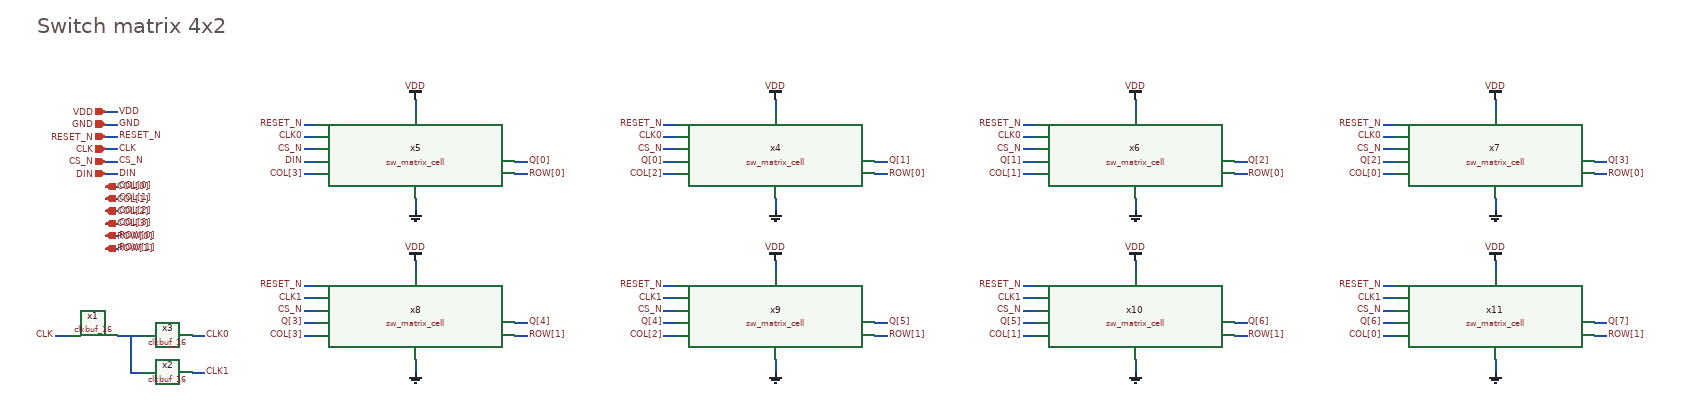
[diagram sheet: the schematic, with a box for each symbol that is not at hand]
v {xschem version=3.4.8RC file_version=1.3
* Copyright 2022 GlobalFoundries PDK Authors
*
* Licensed under the Apache License, Version 2.0 (the "License");
* you may not use this file except in compliance with the License.
* You may obtain a copy of the License at
*
*     https://www.apache.org/licenses/LICENSE-2.0
*
* Unless required by applicable law or agreed to in writing, software
* distributed under the License is distributed on an "AS IS" BASIS,
* WITHOUT WARRANTIES OR CONDITIONS OF ANY KIND, either express or implied.
* See the License for the specific language governing permissions and
* limitations under the License.

}
G {}
K {}
V {}
S {}
F {}
E {}
T {Switch matrix 4x2} 70 -790 0 0 1 1 {}
N 680 -660 680 -640 {lab=VDD}
N 680 -500 680 -480 {lab=GND}
N 500 -620 520 -620 {lab=RESET_N}
N 500 -600 520 -600 {lab=CLK0}
N 500 -580 520 -580 {lab=CS_N}
N 500 -560 520 -560 {lab=DIN}
N 100 -280 120 -280 {lab=CLK}
N 200 -280 240 -280 {lab=#net5}
N 320 -280 340 -280 {lab=CLK0}
N 500 -540 520 -540 {lab=COL[3]}
N 840 -540 860 -540 {lab=ROW[0]}
N 840 -560 860 -560 {lab=Q[0]}
N 320 -220 340 -220 {lab=CLK1}
N 220 -220 240 -220 {lab=#net5}
N 220 -280 220 -220 {lab=#net5}
N 1260 -660 1260 -640 {lab=VDD}
N 1260 -500 1260 -480 {lab=GND}
N 1080 -620 1100 -620 {lab=RESET_N}
N 1080 -600 1100 -600 {lab=CLK0}
N 1080 -580 1100 -580 {lab=CS_N}
N 1080 -560 1100 -560 {lab=Q[0]}
N 1080 -540 1100 -540 {lab=COL[2]}
N 1420 -540 1440 -540 {lab=ROW[0]}
N 1420 -560 1440 -560 {lab=Q[1]}
N 1840 -660 1840 -640 {lab=VDD}
N 1840 -500 1840 -480 {lab=GND}
N 1660 -620 1680 -620 {lab=RESET_N}
N 1660 -600 1680 -600 {lab=CLK0}
N 1660 -580 1680 -580 {lab=CS_N}
N 1660 -560 1680 -560 {lab=Q[1]}
N 1660 -540 1680 -540 {lab=COL[1]}
N 2000 -540 2020 -540 {lab=ROW[0]}
N 2000 -560 2020 -560 {lab=Q[2]}
N 2420 -660 2420 -640 {lab=VDD}
N 2420 -500 2420 -480 {lab=GND}
N 2240 -620 2260 -620 {lab=RESET_N}
N 2240 -600 2260 -600 {lab=CLK0}
N 2240 -580 2260 -580 {lab=CS_N}
N 2240 -560 2260 -560 {lab=Q[2]}
N 2240 -540 2260 -540 {lab=COL[0]}
N 2580 -540 2600 -540 {lab=ROW[0]}
N 2580 -560 2600 -560 {lab=Q[3]}
N 680 -400 680 -380 {lab=VDD}
N 680 -240 680 -220 {lab=GND}
N 500 -360 520 -360 {lab=RESET_N}
N 500 -340 520 -340 {lab=CLK1}
N 500 -320 520 -320 {lab=CS_N}
N 500 -300 520 -300 {lab=Q[3]}
N 500 -280 520 -280 {lab=COL[3]}
N 840 -280 860 -280 {lab=ROW[1]}
N 840 -300 860 -300 {lab=Q[4]}
N 1260 -400 1260 -380 {lab=VDD}
N 1260 -240 1260 -220 {lab=GND}
N 1080 -360 1100 -360 {lab=RESET_N}
N 1080 -340 1100 -340 {lab=CLK1}
N 1080 -320 1100 -320 {lab=CS_N}
N 1080 -300 1100 -300 {lab=Q[4]}
N 1080 -280 1100 -280 {lab=COL[2]}
N 1420 -280 1440 -280 {lab=ROW[1]}
N 1420 -300 1440 -300 {lab=Q[5]}
N 1840 -400 1840 -380 {lab=VDD}
N 1840 -240 1840 -220 {lab=GND}
N 1660 -360 1680 -360 {lab=RESET_N}
N 1660 -340 1680 -340 {lab=CLK1}
N 1660 -320 1680 -320 {lab=CS_N}
N 1660 -300 1680 -300 {lab=Q[5]}
N 1660 -280 1680 -280 {lab=COL[1]}
N 2000 -280 2020 -280 {lab=ROW[1]}
N 2000 -300 2020 -300 {lab=Q[6]}
N 2420 -400 2420 -380 {lab=VDD}
N 2420 -240 2420 -220 {lab=GND}
N 2240 -360 2260 -360 {lab=RESET_N}
N 2240 -340 2260 -340 {lab=CLK1}
N 2240 -320 2260 -320 {lab=CS_N}
N 2240 -300 2260 -300 {lab=Q[6]}
N 2240 -280 2260 -280 {lab=COL[0]}
N 2580 -280 2600 -280 {lab=ROW[1]}
N 2580 -300 2600 -300 {lab=Q[7]}
N 180 -600 200 -600 {lab=RESET_N}
N 180 -580 200 -580 {lab=CLK}
N 180 -560 200 -560 {lab=CS_N}
N 180 -540 200 -540 {lab=DIN}
N 180 -520 200 -520 {lab=COL[0]}
N 180 -620 200 -620 {lab=GND}
N 180 -640 200 -640 {lab=VDD}
N 180 -500 200 -500 {lab=COL[1]}
N 180 -480 200 -480 {lab=COL[3]}
N 180 -460 200 -460 {lab=COL[3]}
N 180 -440 200 -440 {lab=COL[0]}
N 180 -420 200 -420 {lab=COL[1]}
C {devices/title.sym} 160 -30 0 0 {name=l5 author="Yutaka KOTANI"}
C {gnd.sym} 680 -480 0 0 {name=l7 lab=GND}
C {vdd.sym} 680 -660 0 0 {name=l8 lab=VDD}
C {lab_pin.sym} 500 -620 0 0 {name=p6 sig_type=std_logic lab=RESET_N}
C {lab_pin.sym} 860 -540 0 1 {name=p2 sig_type=std_logic lab=ROW[0]}
C {libs/gf180mcu_stdcells/clkbuf_16.sym} 160 -280 0 0 {name=x1 VGND=VGND VNB=VNB VPB=VPB VPWR=VPWR prefix=gf180mcu_fd_sc_mcu7t5v0__ }
C {libs/gf180mcu_stdcells/clkbuf_16.sym} 280 -280 0 0 {name=x3 VGND=VGND VNB=VNB VPB=VPB VPWR=VPWR prefix=gf180mcu_fd_sc_mcu7t5v0__ }
C {sw_matrix_cell.sym} 680 -580 0 0 {name=x5}
C {lab_pin.sym} 500 -580 0 0 {name=p18 sig_type=std_logic lab=CS_N}
C {lab_pin.sym} 500 -560 0 0 {name=p19 sig_type=std_logic lab=DIN}
C {lab_pin.sym} 100 -280 0 0 {name=p3 sig_type=std_logic lab=CLK}
C {lab_pin.sym} 500 -540 0 0 {name=p8 sig_type=std_logic lab=COL[3]}
C {lab_pin.sym} 860 -560 0 1 {name=p7 sig_type=std_logic lab=Q[0]}
C {lab_pin.sym} 500 -600 0 0 {name=p9 sig_type=std_logic lab=CLK0}
C {lab_pin.sym} 340 -280 0 1 {name=p12 sig_type=std_logic lab=CLK0}
C {libs/gf180mcu_stdcells/clkbuf_16.sym} 280 -220 0 0 {name=x2 VGND=VGND VNB=VNB VPB=VPB VPWR=VPWR prefix=gf180mcu_fd_sc_mcu7t5v0__ }
C {lab_pin.sym} 340 -220 0 1 {name=p20 sig_type=std_logic lab=CLK1}
C {gnd.sym} 1260 -480 0 0 {name=l13 lab=GND}
C {vdd.sym} 1260 -660 0 0 {name=l15 lab=VDD}
C {lab_pin.sym} 1080 -620 0 0 {name=p21 sig_type=std_logic lab=RESET_N}
C {lab_pin.sym} 1440 -540 0 1 {name=p22 sig_type=std_logic lab=ROW[0]}
C {sw_matrix_cell.sym} 1260 -580 0 0 {name=x4}
C {lab_pin.sym} 1080 -580 0 0 {name=p23 sig_type=std_logic lab=CS_N}
C {lab_pin.sym} 1080 -560 0 0 {name=p24 sig_type=std_logic lab=Q[0]}
C {lab_pin.sym} 1080 -540 0 0 {name=p25 sig_type=std_logic lab=COL[2]}
C {lab_pin.sym} 1440 -560 0 1 {name=p26 sig_type=std_logic lab=Q[1]}
C {lab_pin.sym} 1080 -600 0 0 {name=p27 sig_type=std_logic lab=CLK0}
C {gnd.sym} 1840 -480 0 0 {name=l18 lab=GND}
C {vdd.sym} 1840 -660 0 0 {name=l19 lab=VDD}
C {lab_pin.sym} 1660 -620 0 0 {name=p28 sig_type=std_logic lab=RESET_N}
C {lab_pin.sym} 2020 -540 0 1 {name=p29 sig_type=std_logic lab=ROW[0]}
C {sw_matrix_cell.sym} 1840 -580 0 0 {name=x6}
C {lab_pin.sym} 1660 -580 0 0 {name=p30 sig_type=std_logic lab=CS_N}
C {lab_pin.sym} 1660 -560 0 0 {name=p31 sig_type=std_logic lab=Q[1]}
C {lab_pin.sym} 1660 -540 0 0 {name=p32 sig_type=std_logic lab=COL[1]}
C {lab_pin.sym} 2020 -560 0 1 {name=p33 sig_type=std_logic lab=Q[2]}
C {lab_pin.sym} 1660 -600 0 0 {name=p34 sig_type=std_logic lab=CLK0}
C {gnd.sym} 2420 -480 0 0 {name=l20 lab=GND}
C {vdd.sym} 2420 -660 0 0 {name=l21 lab=VDD}
C {lab_pin.sym} 2240 -620 0 0 {name=p35 sig_type=std_logic lab=RESET_N}
C {lab_pin.sym} 2600 -540 0 1 {name=p36 sig_type=std_logic lab=ROW[0]}
C {sw_matrix_cell.sym} 2420 -580 0 0 {name=x7}
C {lab_pin.sym} 2240 -580 0 0 {name=p37 sig_type=std_logic lab=CS_N}
C {lab_pin.sym} 2240 -560 0 0 {name=p38 sig_type=std_logic lab=Q[2]}
C {lab_pin.sym} 2240 -540 0 0 {name=p39 sig_type=std_logic lab=COL[0]}
C {lab_pin.sym} 2600 -560 0 1 {name=p40 sig_type=std_logic lab=Q[3]}
C {lab_pin.sym} 2240 -600 0 0 {name=p41 sig_type=std_logic lab=CLK0}
C {gnd.sym} 680 -220 0 0 {name=l22 lab=GND}
C {vdd.sym} 680 -400 0 0 {name=l23 lab=VDD}
C {lab_pin.sym} 500 -360 0 0 {name=p42 sig_type=std_logic lab=RESET_N}
C {lab_pin.sym} 860 -280 0 1 {name=p43 sig_type=std_logic lab=ROW[1]}
C {sw_matrix_cell.sym} 680 -320 0 0 {name=x8}
C {lab_pin.sym} 500 -320 0 0 {name=p44 sig_type=std_logic lab=CS_N}
C {lab_pin.sym} 500 -300 0 0 {name=p45 sig_type=std_logic lab=Q[3]}
C {lab_pin.sym} 500 -280 0 0 {name=p46 sig_type=std_logic lab=COL[3]}
C {lab_pin.sym} 860 -300 0 1 {name=p47 sig_type=std_logic lab=Q[4]}
C {lab_pin.sym} 500 -340 0 0 {name=p48 sig_type=std_logic lab=CLK1}
C {gnd.sym} 1260 -220 0 0 {name=l24 lab=GND}
C {vdd.sym} 1260 -400 0 0 {name=l25 lab=VDD}
C {lab_pin.sym} 1080 -360 0 0 {name=p49 sig_type=std_logic lab=RESET_N}
C {lab_pin.sym} 1440 -280 0 1 {name=p50 sig_type=std_logic lab=ROW[1]}
C {sw_matrix_cell.sym} 1260 -320 0 0 {name=x9}
C {lab_pin.sym} 1080 -320 0 0 {name=p51 sig_type=std_logic lab=CS_N}
C {lab_pin.sym} 1080 -300 0 0 {name=p52 sig_type=std_logic lab=Q[4]}
C {lab_pin.sym} 1080 -280 0 0 {name=p53 sig_type=std_logic lab=COL[2]}
C {lab_pin.sym} 1440 -300 0 1 {name=p54 sig_type=std_logic lab=Q[5]}
C {lab_pin.sym} 1080 -340 0 0 {name=p55 sig_type=std_logic lab=CLK1}
C {gnd.sym} 1840 -220 0 0 {name=l26 lab=GND}
C {vdd.sym} 1840 -400 0 0 {name=l27 lab=VDD}
C {lab_pin.sym} 1660 -360 0 0 {name=p56 sig_type=std_logic lab=RESET_N}
C {lab_pin.sym} 2020 -280 0 1 {name=p57 sig_type=std_logic lab=ROW[1]}
C {sw_matrix_cell.sym} 1840 -320 0 0 {name=x10}
C {lab_pin.sym} 1660 -320 0 0 {name=p58 sig_type=std_logic lab=CS_N}
C {lab_pin.sym} 1660 -300 0 0 {name=p59 sig_type=std_logic lab=Q[5]}
C {lab_pin.sym} 1660 -280 0 0 {name=p60 sig_type=std_logic lab=COL[1]}
C {lab_pin.sym} 2020 -300 0 1 {name=p61 sig_type=std_logic lab=Q[6]}
C {lab_pin.sym} 1660 -340 0 0 {name=p62 sig_type=std_logic lab=CLK1}
C {gnd.sym} 2420 -220 0 0 {name=l28 lab=GND}
C {vdd.sym} 2420 -400 0 0 {name=l29 lab=VDD}
C {lab_pin.sym} 2240 -360 0 0 {name=p63 sig_type=std_logic lab=RESET_N}
C {lab_pin.sym} 2600 -280 0 1 {name=p64 sig_type=std_logic lab=ROW[1]}
C {sw_matrix_cell.sym} 2420 -320 0 0 {name=x11}
C {lab_pin.sym} 2240 -320 0 0 {name=p65 sig_type=std_logic lab=CS_N}
C {lab_pin.sym} 2240 -300 0 0 {name=p66 sig_type=std_logic lab=Q[6]}
C {lab_pin.sym} 2240 -280 0 0 {name=p67 sig_type=std_logic lab=COL[0]}
C {lab_pin.sym} 2600 -300 0 1 {name=p68 sig_type=std_logic lab=Q[7]}
C {lab_pin.sym} 2240 -340 0 0 {name=p69 sig_type=std_logic lab=CLK1}
C {lab_pin.sym} 200 -600 0 1 {name=p70 sig_type=std_logic lab=RESET_N}
C {lab_pin.sym} 200 -560 0 1 {name=p71 sig_type=std_logic lab=CS_N}
C {lab_pin.sym} 200 -540 0 1 {name=p72 sig_type=std_logic lab=DIN}
C {lab_pin.sym} 200 -520 0 1 {name=p73 sig_type=std_logic lab=COL[0]}
C {lab_pin.sym} 200 -580 0 1 {name=p74 sig_type=std_logic lab=CLK}
C {lab_pin.sym} 200 -620 0 1 {name=p75 sig_type=std_logic lab=GND}
C {lab_pin.sym} 200 -640 0 1 {name=p76 sig_type=std_logic lab=VDD}
C {ipin.sym} 180 -640 0 0 {name=p77 lab=VDD}
C {ipin.sym} 180 -620 0 0 {name=p78 lab=GND}
C {ipin.sym} 180 -600 0 0 {name=p79 lab=RESET_N}
C {ipin.sym} 180 -580 0 0 {name=p80 lab=CLK}
C {ipin.sym} 180 -560 0 0 {name=p81 lab=CS_N}
C {ipin.sym} 180 -540 0 0 {name=p82 lab=DIN}
C {iopin.sym} 180 -520 0 1 {name=p83 lab=COL[0]}
C {lab_pin.sym} 200 -500 0 1 {name=p84 sig_type=std_logic lab=COL[1]}
C {iopin.sym} 180 -500 0 1 {name=p85 lab=COL[1]}
C {lab_pin.sym} 200 -480 0 1 {name=p86 sig_type=std_logic lab=COL[2]}
C {iopin.sym} 180 -480 0 1 {name=p87 lab=COL[2]}
C {lab_pin.sym} 200 -460 0 1 {name=p88 sig_type=std_logic lab=COL[3]}
C {iopin.sym} 180 -460 0 1 {name=p89 lab=COL[3]}
C {lab_pin.sym} 200 -440 0 1 {name=p90 sig_type=std_logic lab=ROW[0]}
C {iopin.sym} 180 -440 0 1 {name=p91 lab=ROW[0]}
C {lab_pin.sym} 200 -420 0 1 {name=p92 sig_type=std_logic lab=ROW[1]}
C {iopin.sym} 180 -420 0 1 {name=p93 lab=ROW[1]}
